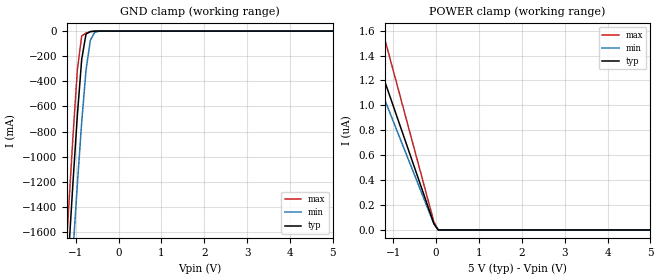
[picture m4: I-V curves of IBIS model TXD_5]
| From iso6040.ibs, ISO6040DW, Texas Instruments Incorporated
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|   TXD_5 Model
[Model]   TXD_5
Model_type   Input
|Signals   TXD
Vinl =  1.500V
Vinh =  3.500V
|   typ   min   max
C_comp   1.3pF   1.1pF   1.5pF
|   typ   min   max
[Temperature Range]   27   -55   150
[Voltage range]   5.0V   4.5V   5.5V
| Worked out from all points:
|   GND clamp passes 1 mA (typ) near -0.57 V on its own axis
[GND_clamp]
|Voltage   I(typ)   I(min)   I(max)
-5V       -18.88A    -18.42A    -19.4A
-1.263V   -2.337A    -2.857A    -2.002A
-1.162V   -1.76A     -2.296A    -1.406A
-1.061V   -1.199A    -1.748A    -830.6mA
-960mV    -669.8mA   -1.219A    -310.2mA
-859mV    -225.7mA   -725.6mA   -38.72mA
-758mV    -23.33mA   -311.2mA   -16.13mA
-657mV    -3.585mA   -73.04mA   -5.621mA
-556mV    -561.7uA   -9.428mA   -751.6uA
-455mV    -35.58uA   -731.5uA   -23.6uA
5V        0A         0A         -640.1nA
[POWER_clamp]
|Voltage   I(typ)   I(min)   I(max)
-5V       4.982uA    4.351uA    6.403uA
-1.868V   1.861uA    1.627uA    2.392uA
-1.767V   1.761uA    1.54uA     2.263uA
-1.666V   1.66uA     1.452uA    2.133uA
-1.565V   1.559uA    1.364uA    2.004uA
-1.262V   1.258uA    1.101uA    1.616uA
-1.161V   1.157uA    1.013uA    1.487uA
-50mV     49.91nA    47.77nA    64.12nA
51mV      0A         0A         0A
5V        0A         0A         0A
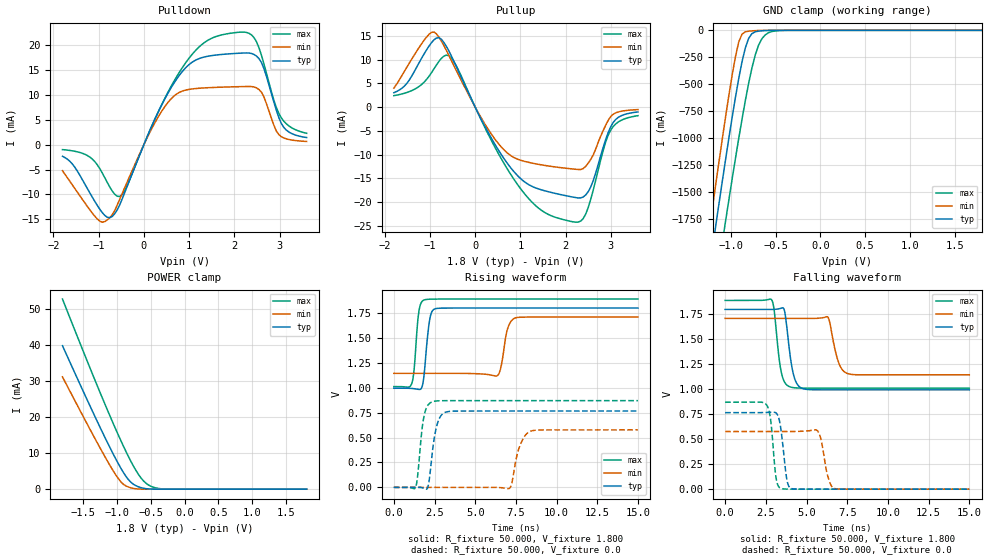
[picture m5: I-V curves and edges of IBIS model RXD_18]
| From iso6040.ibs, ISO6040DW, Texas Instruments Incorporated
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|   RXD_18 Model
[Model]   RXD_18
Model_type   3-state
| Signals   RXD
| variable   typ   min   max
C_comp   2.1pF   1.7pF   2.5pF
|   typ   min   max
[Temperature Range]   25.0   -55   150
[Voltage range]   1.8V   1.71V   1.89V
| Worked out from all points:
|   slope of the pulldown table from 0 to 0.27 V, typ, clamps not added: 47.8 ohm
|   slope of the pullup table from 0 to 0.27 V, typ, clamps not added: 53.6 ohm
|   GND clamp passes 1 mA (typ) near -0.57 V on its own axis
|   POWER clamp passes 1 mA (typ) near -0.72 V on its own axis
|   rising waveform, R_fixture 50.000, V_fixture 1.800: 20-80 % time 287ps typ, 355ps min, 252ps max; typ from 0.995 V to 1.8 V
|   rising waveform, R_fixture 50.000, V_fixture 0.0: 20-80 % time 395ps typ, 530ps min, 333ps max; typ from 0 V to 0.766 V
|   falling waveform, R_fixture 50.000, V_fixture 1.800: 20-80 % time 410ps typ, 485ps min, 366ps max; typ from 1.8 V to 0.995 V
|   falling waveform, R_fixture 50.000, V_fixture 0.0: 20-80 % time 325ps typ, 398ps min, 288ps max; typ from 0.766 V to 0 V
[Pulldown]
|Voltage   I(typ)   I(min)   I(max)
-1.8V     -2.335mA   -5.244mA   -989.9uA
-1.03V    -12.24mA   -14.97mA   -4.049mA
-700mV    -14.46mA   -14.1mA    -9.325mA
-425mV    -9.688mA   -8.683mA   -9.257mA
180mV     3.852mA    3.341mA    3.855mA
620mV     11.74mA    9.4mA      12.04mA
1.28V     17.53mA    11.41mA    20.16mA
2.105V    18.43mA    11.69mA    22.65mA
2.38V     18.38mA    11.71mA    22.13mA
2.6V      16.56mA    10.59mA    18.04mA
3.04V     4.29mA     1.616mA    5.413mA
3.6V      1.438mA    652.1uA    2.296mA
[Pullup]
|Voltage   I(typ)   I(min)   I(max)
-1.8V     3.041mA    4.007mA    2.417mA
-1.515V   4.975mA    8.377mA    3.081mA
-1.075V   12.1mA     14.79mA    5.848mA
-800mV    14.65mA    14.74mA    9.683mA
-470mV    9.632mA    8.733mA    9.587mA
630mV     -10.76mA   -8.948mA   -11.76mA
1.4V      -17.26mA   -12.07mA   -21.3mA
2.225V    -19.09mA   -13.12mA   -24.28mA
2.39V     -18.95mA   -12.95mA   -23.5mA
2.555V    -16.85mA   -11.04mA   -19.46mA
2.995V    -4.181mA   -2.009mA   -4.878mA
3.6V      -1.015mA   -518.7uA   -1.803mA
[GND_clamp]
|Voltage   I(typ)   I(min)   I(max)
-1.8V     -5.55A     -5.263A    -6.015A
-1.245V   -2.254A    -1.881A    -2.805A
-1.208V   -2.04A     -1.662A    -2.596A
-1.171V   -1.829A    -1.444A    -2.389A
-1.06V    -1.206A    -809.9mA   -1.779A
-986mV    -811.2mA   -418.7mA   -1.384A
-912mV    -448.5mA   -108.4mA   -1.005A
-838mV    -162.4mA   -13.59mA   -652mA
-764mV    -29.97mA   -5.269mA   -347.9mA
-690mV    -7.462mA   -1.484mA   -136.9mA
-542mV    -545uA     -4.781uA   -11.14mA
1.8V      0A         0A         0A
[POWER_clamp]
|Voltage   I(typ)   I(min)   I(max)
-1.8V     39.81mA    31.16mA    52.76mA
-1.493V   27.11mA    20.12mA    38.23mA
-1.234V   16.69mA    11.05mA    26.29mA
-1.086V   11.01mA    6.141mA    19.71mA
-975mV    7.015mA    2.889mA    14.96mA
-901mV    4.615mA    1.347mA    11.92mA
-790mV    1.893mA    366.5uA    7.681mA
-679mV    650uA      40.99uA    4.075mA
-568mV    138uA      1.396uA    1.643mA
-457mV    11.68uA    20.67nA    519.2uA
-272mV    53.44nA    77.19pA    26.85uA
1.8V      0A         0A         0A
[Ramp]
| variable   typ   min   max
dV/dt_r   0.460/0.395n   0.346/0.528n   0.522/0.333n
dV/dt_f   0.483/0.409n   0.339/0.484n   0.527/0.366n
R_load = 50.000
[Rising Waveform]
R_fixture= 50.000
V_fixture= 1.800
V_fixture_min= 1.710
V_fixture_max= 1.890
|time   V(typ)   V(min)   V(max)
0s        994.8mV    1.144V     1.012V
1.111ns   992.6mV    1.145V     1.046V
1.544ns   982.8mV    1.145V     1.769V
1.867ns   1.141V     1.145V     1.881V
2.193ns   1.672V     1.145V     1.889V
2.573ns   1.794V     1.145V     1.89V
6.36ns    1.8V       1.122V     1.89V
6.998ns   1.8V       1.597V     1.89V
7.508ns   1.8V       1.703V     1.89V
15ns      1.8V       1.71V      1.89V
[Rising Waveform]
R_fixture= 50.000
V_fixture= 0.0
V_fixture_min= 0.0
V_fixture_max= 0.0
|time   V(typ)   V(min)   V(max)
0s        3.665nV    1.985nV    1.128uV
1.339ns   158.3uV    -9.392nV   995.5uV
1.849ns   -8.797mV   -29.83nV   709.4mV
2.349ns   325.9mV    -65.49nV   857.4mV
2.698ns   651mV      -116.4nV   867.9mV
3.268ns   758.5mV    -227.3nV   870.1mV
7.107ns   766.2mV    -9.832mV   870.4mV
7.732ns   766.2mV    411.7mV    870.4mV
8.452ns   766.2mV    566.5mV    870.4mV
15ns      766.2mV    577.1mV    870.4mV
[Falling Waveform]
R_fixture= 50.000
V_fixture= 1.800
V_fixture_min= 1.710
V_fixture_max= 1.890
|time   V(typ)   V(min)   V(max)
0s        1.8V       1.71V      1.89V
2.855ns   1.8V       1.71V      1.896V
3.37ns    1.809V     1.71V      1.244V
3.62ns    1.8V       1.71V      1.081V
3.98ns    1.353V     1.71V      1.025V
4.52ns    1.032V     1.71V      1.013V
6.31ns    994.8mV    1.722V     1.012V
6.948ns   994.8mV    1.279V     1.012V
7.518ns   994.8mV    1.158V     1.012V
15ns      994.8mV    1.145V     1.012V
[Falling Waveform]
R_fixture= 50.000
V_fixture= 0.0
V_fixture_min= 0.0
V_fixture_max= 0.0
|time   V(typ)   V(min)   V(max)
0s        766.2mV    577.1mV    870.4mV
2.565ns   768.3mV    577.1mV    838.8mV
2.784ns   770.1mV    577.1mV    706mV
3.132ns   762.2mV    577.1mV    110.3mV
3.425ns   599.7mV    577.1mV    7.388mV
3.779ns   108.5mV    577.1mV    853.8uV
4.046ns   7.887mV    577.4mV    232.5uV
5.689ns   12.87uV    581.8mV    16.19uV
6.703ns   11.96uV    7.317mV    15.94uV
15ns      11.4uV     9.467uV    15.29uV
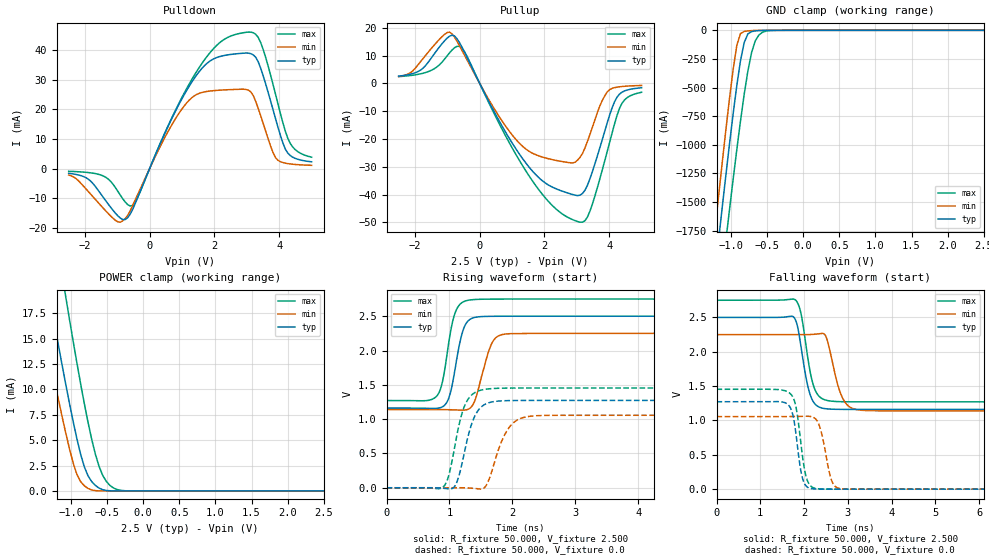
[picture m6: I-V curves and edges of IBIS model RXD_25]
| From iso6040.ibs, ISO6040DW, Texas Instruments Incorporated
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|   RXD_25 Model
[Model]   RXD_25
Model_type   3-state
| Signals   RXD
| variable   typ   min   max
C_comp   2.1pF   1.7pF   2.5pF
|   typ   min   max
[Temperature Range]   25.0   -55   150
[Voltage range]   2.5V   2.25V   2.75V
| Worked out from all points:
|   slope of the pulldown table from 0 to 0.375 V, typ, clamps not added: 39 ohm
|   slope of the pullup table from 0 to 0.375 V, typ, clamps not added: 43.6 ohm
|   GND clamp passes 1 mA (typ) near -0.57 V on its own axis
|   POWER clamp passes 1 mA (typ) near -0.72 V on its own axis
|   rising waveform, R_fixture 50.000, V_fixture 2.500: 20-80 % time 168ps typ, 202ps min, 165ps max; typ from 1.16 V to 2.5 V
|   rising waveform, R_fixture 50.000, V_fixture 0.0: 20-80 % time 216ps typ, 261ps min, 211ps max; typ from 0 V to 1.27 V
|   falling waveform, R_fixture 50.000, V_fixture 2.500: 20-80 % time 223ps typ, 268ps min, 228ps max; typ from 2.5 V to 1.16 V
|   falling waveform, R_fixture 50.000, V_fixture 0.0: 20-80 % time 166ps typ, 203ps min, 185ps max; typ from 1.27 V to 0 V
[Pulldown]
|Voltage   I(typ)   I(min)   I(max)
-2.5V     -1.625mA   -2.206mA   -947.1uA
-1.892V   -3.611mA   -7.805mA   -1.365mA
-1.36V    -10.84mA   -14.29mA   -2.937mA
-752mV    -17.27mA   -16.94mA   -11.38mA
-448mV    -11.9mA    -10.69mA   -11.47mA
1.224V    27.93mA    23.18mA    28.67mA
2.136V    37.82mA    26.51mA    42.35mA
3.048V    39.08mA    26.51mA    46.2mA
3.428V    33.95mA    17.88mA    42.64mA
3.884V    16.98mA    3.713mA    25.25mA
4.34V     4.393mA    1.548mA    8.519mA
5V        2.273mA    1.082mA    3.83mA
[Pullup]
|Voltage   I(typ)   I(min)   I(max)
-2.5V     2.588mA    2.465mA    2.421mA
-1.764V   5.301mA    8.681mA    3.583mA
-1.004V   16.25mA    18.26mA    9.886mA
-548mV    13.08mA    11.9mA     12.68mA
592mV     -13.29mA   -11.78mA   -14.23mA
1.352V    -27.51mA   -22.93mA   -30.14mA
2.264V    -37.45mA   -27.51mA   -44.19mA
3.1V      -40.23mA   -26.6mA    -49.96mA
3.404V    -34.37mA   -18.4mA    -46.03mA
3.936V    -14.32mA   -3.13mA    -24.63mA
4.392V    -3.202mA   -1.146mA   -7.23mA
5V        -1.582mA   -764.8uA   -3.201mA
[GND_clamp]
|Voltage   I(typ)   I(min)   I(max)
-2.5V     -9.36A     -9.468A    -9.252A
-1.225V   -2.138A    -1.762A    -2.692A
-1.174V   -1.846A    -1.462A    -2.406A
-1.123V   -1.557A    -1.166A    -2.123A
-1.072V   -1.272A    -876.6mA   -1.844A
-1.021V   -995.4mA   -598.5mA   -1.569A
-919mV    -480.7mA   -130.4mA   -1.04A
-817mV    -106.9mA   -9.777mA   -559.2mA
-715mV    -11.09mA   -2.487mA   -194.8mA
-664mV    -5.107mA   -761uA     -92.14mA
-511mV    -239.3uA   -922.2nA   -6.444mA
2.5V      0A         0A         0A
[POWER_clamp]
|Voltage   I(typ)   I(min)   I(max)
-2.5V     69.34mA    56.76mA    86.62mA
-1.478V   26.5mA     19.58mA    37.53mA
-1.427V   24.42mA    17.77mA    35.15mA
-1.325V   20.31mA    14.19mA    30.44mA
-1.274V   18.27mA    12.42mA    28.11mA
-1.07V    10.41mA    5.638mA    19.01mA
-917mV    5.107mA    1.609mA    12.57mA
-764mV    1.488mA    247.4uA    6.764mA
-662mV    538.5uA    25.96uA    3.612mA
-560mV    119uA      1.058uA    1.524mA
-356mV    729.5nA    369.7pA    125.3uA
2.5V      0A         0A         0A
[Ramp]
| variable   typ   min   max
dV/dt_r   0.764/0.216n   0.634/0.261n   0.872/0.210n
dV/dt_f   0.803/0.224n   0.666/0.269n   0.887/0.228n
R_load = 50.000
[Rising Waveform]
R_fixture= 50.000
V_fixture= 2.500
V_fixture_min= 2.250
V_fixture_max= 2.750
|time   V(typ)   V(min)   V(max)
0s        1.161V     1.141V     1.271V
726ps     1.156V     1.14V      1.289V
843ps     1.164V     1.14V      1.405V
929ps     1.209V     1.138V     1.744V
1.094ns   1.752V     1.134V     2.556V
1.21ns    2.276V     1.131V     2.704V
1.338ns   2.461V     1.168V     2.738V
1.672ns   2.499V     2.101V     2.749V
1.892ns   2.5V       2.241V     2.75V
15ns      2.5V       2.25V      2.75V
[Rising Waveform]
R_fixture= 50.000
V_fixture= 0.0
V_fixture_min= 0.0
V_fixture_max= 0.0
|time   V(typ)   V(min)   V(max)
0s        3.613nV    2.041nV    1.082uV
866ps     -4.429mV   81.09uV    -8.397mV
971ps     -14.44mV   122.1uV    124.7mV
1.064ns   85.77uV    175.5uV    499.1mV
1.268ns   637.6mV    -1.639mV   1.246V
1.42ns    1.074V     -11.73mV   1.395V
1.613ns   1.235V     84.37mV    1.44V
1.944ns   1.27V      871.9mV    1.453V
2.374ns   1.273V     1.05V      1.454V
15ns      1.273V     1.057V     1.454V
[Falling Waveform]
R_fixture= 50.000
V_fixture= 2.500
V_fixture_min= 2.250
V_fixture_max= 2.750
|time   V(typ)   V(min)   V(max)
0s        2.5V       2.25V      2.75V
1.813ns   2.449V     2.25V      2.748V
1.932ns   2.063V     2.25V      2.548V
2.149ns   1.356V     2.252V     1.673V
2.31ns    1.207V     2.26V      1.376V
2.476ns   1.173V     2.248V     1.3V
2.567ns   1.167V     2.073V     1.286V
2.881ns   1.161V     1.323V     1.273V
3.301ns   1.161V     1.149V     1.271V
15ns      1.161V     1.141V     1.271V
[Falling Waveform]
R_fixture= 50.000
V_fixture= 0.0
V_fixture_min= 0.0
V_fixture_max= 0.0
|time   V(typ)   V(min)   V(max)
0s        1.273V     1.057V     1.454V
1.696ns   1.173V     1.058V     1.383V
1.818ns   784.7mV    1.059V     1.185V
1.978ns   128.7mV    1.061V     408.3mV
2.104ns   18.83mV    1.061V     84.37mV
2.297ns   1.833mV    995.1mV    7.505mV
2.399ns   726.6uV    813.4mV    2.802mV
2.625ns   124.8uV    132.4mV    493.8uV
2.819ns   38.6uV     8.003mV    140uV
15ns      13.64uV    11.87uV    18.83uV
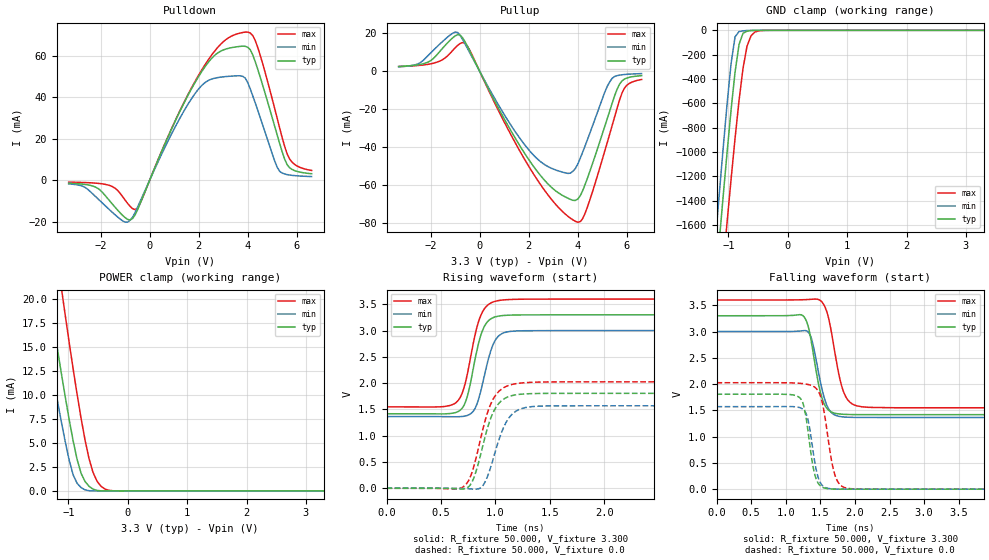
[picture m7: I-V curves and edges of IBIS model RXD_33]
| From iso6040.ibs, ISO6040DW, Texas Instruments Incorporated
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|   RXD_33 Model
[Model]   RXD_33
Model_type   3-state
| Signals   RXD
Vmeas = 2.2V   |Reference voltage for timing measurements
Cref = 15pF   |Timing specification test load capacitance value
Vref = 0   |Timing specification test load voltage; GND
| variable   typ   min   max
C_comp   2.1pF   1.7pF   2.5pF
|   typ   min   max
[Temperature Range]   25.0   -55   150
[Voltage range]   3.3V   3.0V   3.6V
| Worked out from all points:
|   slope of the pulldown table from 0 to 0.495 V, typ, clamps not added: 35.3 ohm
|   slope of the pullup table from 0 to 0.495 V, typ, clamps not added: 38.9 ohm
|   GND clamp passes 1 mA (typ) near -0.56 V on its own axis
|   POWER clamp passes 1 mA (typ) near -0.72 V on its own axis
|   rising waveform, R_fixture 50.000, V_fixture 3.300: 20-80 % time 120ps typ, 123ps min, 130ps max; typ from 1.42 V to 3.3 V
|   rising waveform, R_fixture 50.000, V_fixture 0.0: 20-80 % time 152ps typ, 156ps min, 161ps max; typ from 0 V to 1.81 V
|   falling waveform, R_fixture 50.000, V_fixture 3.300: 20-80 % time 157ps typ, 161ps min, 179ps max; typ from 3.3 V to 1.42 V
|   falling waveform, R_fixture 50.000, V_fixture 0.0: 20-80 % time 122ps typ, 119ps min, 151ps max; typ from 1.81 V to 0 V
[Pulldown]
|Voltage   I(typ)   I(min)   I(max)
-3.3V     -1.393mA   -1.747mA   -927.3uA
-2.2V     -3.331mA   -7.915mA   -1.397mA
-1.6V     -10.36mA   -14.61mA   -2.646mA
-700mV    -18.5mA    -17.91mA   -13.66mA
-400mV    -11.6mA    -10.55mA   -11.49mA
2V        50.13mA    44.09mA    50.76mA
2.8V      61.6mA     49.56mA    64.41mA
3.9V      64.58mA    49.21mA    71.45mA
4.4V      53.72mA    33.93mA    64.23mA
5.3V      17.64mA    4.279mA    25.12mA
5.8V      5.234mA    2.368mA    8.768mA
6.6V      3.148mA    1.78mA     4.728mA
[Pullup]
|Voltage   I(typ)   I(min)   I(max)
-3.3V     2.528mA    2.36mA     2.481mA
-2.1V     4.845mA    8.282mA    3.66mA
-1V       18.57mA    20.6mA     12.32mA
-600mV    15.62mA    14.5mA     14.73mA
1V        -24.99mA   -22.73mA   -26.63mA
2.2V      -50.12mA   -44.19mA   -54.13mA
3.6V      -66.81mA   -53.75mA   -76.32mA
4V        -67.23mA   -48.79mA   -79.4mA
4.4V      -55.98mA   -35.72mA   -71.14mA
5.4V      -16.86mA   -3.719mA   -28.55mA
5.9V      -4.12mA    -1.716mA   -8.91mA
6.6V      -2.323mA   -1.24mA    -4.34mA
[GND_clamp]
|Voltage   I(typ)   I(min)   I(max)
-3.3V     -12.47A    -12.69A    -12.28A
-1.223V   -2.127A    -1.75A     -2.681A
-1.156V   -1.743A    -1.357A    -2.306A
-1.089V   -1.367A    -972.1mA   -1.937A
-1.022V   -1.001A    -603.8mA   -1.575A
-955mV    -653.8mA   -272.6mA   -1.223A
-888mV    -343.9mA   -53.17mA   -886.9mA
-821mV    -116.4mA   -10.32mA   -576.6mA
-687mV    -7.135mA   -1.384mA   -131mA
-620mV    -2.623mA   -170.6uA   -45.53mA
-486mV    -113.9uA   -230.3nA   -4.203mA
3.3V      0A         0A         0A
[POWER_clamp]
|Voltage   I(typ)   I(min)   I(max)
-3.3V     103.5mA    86.29mA    125.9mA
-1.524V   28.38mA    21.22mA    39.68mA
-1.457V   25.64mA    18.84mA    36.55mA
-1.323V   20.23mA    14.12mA    30.35mA
-1.122V   12.36mA    7.298mA    21.29mA
-1.055V   9.86mA     5.174mA    18.36mA
-921mV    5.233mA    1.682mA    12.73mA
-787mV    1.841mA    351.3uA    7.574mA
-720mV    983.4uA    108.5uA    5.305mA
-519mV    51.34uA    237.9nA    1.021mA
-318mV    230.7nA    159.6pA    64.62uA
3.3V      0A         0A         0A
[Ramp]
| variable   typ   min   max
dV/dt_r   1.084/0.152n   0.942/0.156n   1.215/0.161n
dV/dt_f   1.129/0.157n   0.981/0.161n   1.231/0.179n
R_load = 50.000
[Rising Waveform]
R_fixture= 50.000
V_fixture= 3.300
V_fixture_min= 3.000
V_fixture_max= 3.600
|time   V(typ)   V(min)   V(max)
0s        1.418V     1.364V     1.549V
645ps     1.449V     1.361V     1.643V
692ps     1.517V     1.365V     1.797V
736ps     1.708V     1.382V     2.116V
807ps     2.393V     1.497V     2.86V
870ps     2.938V     1.887V     3.309V
974ps     3.242V     2.712V     3.541V
1.026ns   3.275V     2.891V     3.571V
1.1ns     3.291V     2.972V     3.588V
15ns      3.3V       3V         3.6V
[Rising Waveform]
R_fixture= 50.000
V_fixture= 0.0
V_fixture_min= 0.0
V_fixture_max= 0.0
|time   V(typ)   V(min)   V(max)
0s        4.892nV    2.133nV    1.145uV
700ps     -15.49mV   -3.529mV   21.36mV
789ps     134.2mV    -14.5mV    326.3mV
874ps     720.9mV    25.56mV    1.028V
928ps     1.151V     231.8mV    1.444V
984ps     1.462V     590.8mV    1.714V
1.049ns   1.653V     1.023V     1.875V
1.112ns   1.736V     1.302V     1.949V
1.276ns   1.796V     1.536V     2.01V
15ns      1.806V     1.57V      2.026V
[Falling Waveform]
R_fixture= 50.000
V_fixture= 3.300
V_fixture_min= 3.000
V_fixture_max= 3.600
|time   V(typ)   V(min)   V(max)
0s        3.3V       3V         3.6V
1.247ns   3.304V     3.015V     3.605V
1.363ns   2.86V      2.902V     3.613V
1.502ns   1.839V     2.037V     3.589V
1.62ns    1.504V     1.528V     3.253V
1.768ns   1.432V     1.386V     2.185V
1.832ns   1.425V     1.374V     1.867V
1.931ns   1.421V     1.368V     1.651V
2.101ns   1.418V     1.365V     1.567V
15ns      1.418V     1.364V     1.549V
[Falling Waveform]
R_fixture= 50.000
V_fixture= 0.0
V_fixture_min= 0.0
V_fixture_max= 0.0
|time   V(typ)   V(min)   V(max)
0s        1.806V     1.57V      2.026V
1.195ns   1.749V     1.555V     2.016V
1.255ns   1.611V     1.512V     2.008V
1.308ns   1.239V     1.388V     1.996V
1.427ns   246.7mV    465.1mV    1.933V
1.531ns   36.83mV    68.88mV    1.632V
1.709ns   2.227mV    2.974mV    278.5mV
1.783ns   894.1uV    1.021mV    87.65mV
1.92ns    209.2uV    189.8uV    11.32mV
15ns      15.73uV    13.45uV    22.02uV
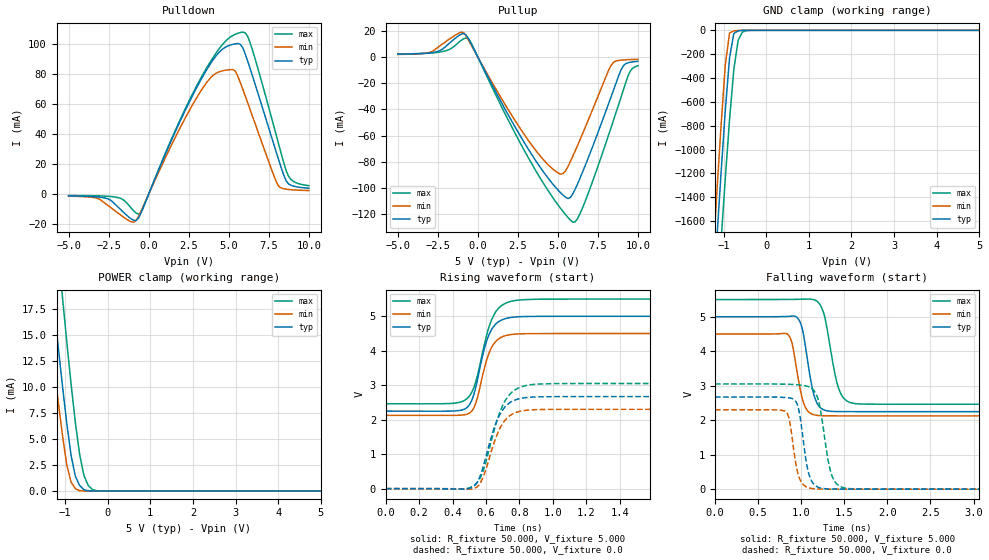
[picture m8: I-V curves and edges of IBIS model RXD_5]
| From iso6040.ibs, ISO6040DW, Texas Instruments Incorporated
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|   RXD_5 Model
[Model]   RXD_5
Model_type   3-state
Vmeas = 2.2V   |Reference voltage for timing measurements
Cref = 15pF   |Timing specification test load capacitance value
Vref = 0   |Timing specification test load voltage; GND
| variable   typ   min   max
C_comp   2.1pF   1.7pF   2.5pF
|   typ   min   max
[Temperature Range]   25.0   -55   150
[Voltage range]   5.0V   4.5V   5.5V
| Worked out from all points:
|   slope of the pulldown table from 0 to 0.75 V, typ, clamps not added: 38.8 ohm
|   slope of the pullup table from 0 to 0.75 V, typ, clamps not added: 41.8 ohm
|   GND clamp passes 1 mA (typ) near -0.56 V on its own axis
|   POWER clamp passes 1 mA (typ) near -0.71 V on its own axis
|   rising waveform, R_fixture 50.000, V_fixture 5.000: 20-80 % time 85.6ps typ, 80.4ps min, 96.1ps max; typ from 2.25 V to 5 V
|   rising waveform, R_fixture 50.000, V_fixture 0.0: 20-80 % time 105ps typ, 101ps min, 113ps max; typ from 0 V to 2.67 V
|   falling waveform, R_fixture 50.000, V_fixture 5.000: 20-80 % time 112ps typ, 105ps min, 135ps max; typ from 5 V to 2.25 V
|   falling waveform, R_fixture 50.000, V_fixture 0.0: 20-80 % time 95.8ps typ, 87ps min, 119ps max; typ from 2.67 V to 0 V
[Pulldown]
|Voltage   I(typ)   I(min)   I(max)
-5V       -1.037mA   -1.214mA   -788.1uA
-2.584V   -2.851mA   -7.029mA   -1.283mA
-1.074V   -16.47mA   -18.37mA   -9.34mA
-470mV    -12.26mA   -11.15mA   -11.94mA
1.946V    48.19mA    43.78mA    49.11mA
3.758V    85.17mA    76.21mA    86.54mA
5.268V    99.87mA    82.99mA    105.8mA
5.872V    97.76mA    70.24mA    108mA
6.476V    79.2mA     52.29mA    96.4mA
8.137V    22.45mA    5.214mA    32.8mA
8.741V    6.971mA    3.227mA    11.94mA
10V       4.07mA     2.512mA    5.759mA
[Pullup]
|Voltage   I(typ)   I(min)   I(max)
-5V       2.195mA    1.994mA    2.343mA
-2.533V   4.197mA    6.987mA    3.547mA
-1.023V   17.52mA    19.05mA    12.9mA
-570mV    13.73mA    12.61mA    13.71mA
4.111V    -87.84mA   -78.53mA   -96.62mA
5.168V    -103.5mA   -89.35mA   -115.5mA
5.923V    -104.5mA   -75.86mA   -126mA
6.527V    -88.13mA   -58.84mA   -115.4mA
8.339V    -29.71mA   -6.022mA   -53.07mA
9.094V    -6.515mA   -2.192mA   -24.88mA
9.547V    -3.88mA    -1.909mA   -10.1mA
10V       -3.261mA   -1.75mA    -6.597mA
[GND_clamp]
|Voltage   I(typ)   I(min)   I(max)
-5V       -19.06A    -19.48A    -18.7A
-1.263V   -2.358A    -1.988A    -2.906A
-1.162V   -1.777A    -1.392A    -2.339A
-1.061V   -1.212A    -815.5mA   -1.784A
-960mV    -678.8mA   -295mA     -1.249A
-859mV    -231.2mA   -22.05mA   -748.6mA
-758mV    -26.06mA   -4.878mA   -326.7mA
-657mV    -4.614mA   -619.2uA   -82.53mA
-556mV    -760.5uA   -9.69uA    -14.38mA
-455mV    -42.02uA   -39.64nA   -2.488mA
5V        0A         0A         0A
[POWER_clamp]
|Voltage   I(typ)   I(min)   I(max)
-5V       176.6mA    149.4mA    210.1mA
-1.464V   25.93mA    19.09mA    36.87mA
-1.363V   21.83mA    15.52mA    32.19mA
-1.262V   17.8mA     12.01mA    27.56mA
-1.06V    10.04mA    5.328mA    18.58mA
-959mV    6.473mA    2.492mA    14.29mA
-858mV    3.393mA    836.2uA    10.23mA
-757mV    1.394mA    220.2uA    6.524mA
-656mV    502.3uA    21.96uA    3.456mA
-454mV    10.82uA    18.37nA    501.2uA
-252mV    27.84nA    146.1pA    18.12uA
5V        0A         0A         0A
[Ramp]
| variable   typ   min   max
dV/dt_r   1.602/0.105n   1.381/0.101n   1.831/0.113n
dV/dt_f   1.651/0.112n   1.424/0.105n   1.823/0.135n
R_load = 50.000
[Rising Waveform]
R_fixture= 50.000
V_fixture= 5.000
V_fixture_min= 4.500
V_fixture_max= 5.500
|time   V(typ)   V(min)   V(max)
0s        2.248V     2.126V     2.462V
475ps     2.314V     2.146V     2.57V
507ps     2.48V      2.213V     2.73V
536ps     2.877V     2.441V     3.061V
589ps     4.042V     3.457V     4.158V
615ps     4.431V     3.893V     4.643V
639ps     4.66V      4.141V     4.952V
712ps     4.927V     4.433V     5.367V
824ps     4.993V     4.494V     5.482V
15ns      5V         4.5V       5.5V
[Rising Waveform]
R_fixture= 50.000
V_fixture= 0.0
V_fixture_min= 0.0
V_fixture_max= 0.0
|time   V(typ)   V(min)   V(max)
0s        7.484nV    3.561nV    2.363uV
443ps     -12.35mV   -6.064mV   -9.918mV
530ps     81.6mV     9.02mV     99.52mV
553ps     227.1mV    78.15mV    215.6mV
582ps     623.4mV    326.8mV    492.7mV
645ps     1.705V     1.282V     1.623V
701ps     2.292V     1.899V     2.42V
772ps     2.568V     2.196V     2.861V
915ps     2.663V     2.295V     3.035V
15ns      2.671V     2.301V     3.051V
[Falling Waveform]
R_fixture= 50.000
V_fixture= 5.000
V_fixture_min= 4.500
V_fixture_max= 5.500
|time   V(typ)   V(min)   V(max)
0s        5V         4.5V       5.5V
828ps     5.008V     4.514V     5.502V
894ps     5.02V      4.233V     5.504V
947ps     4.989V     3.47V      5.506V
1.047ns   4.169V     2.386V     5.512V
1.186ns   2.483V     2.14V      5.444V
1.274ns   2.289V     2.128V     4.989V
1.444ns   2.25V      2.126V     2.86V
1.633ns   2.249V     2.126V     2.479V
15ns      2.249V     2.126V     2.462V
[Falling Waveform]
R_fixture= 50.000
V_fixture= 0.0
V_fixture_min= 0.0
V_fixture_max= 0.0
|time   V(typ)   V(min)   V(max)
0s        2.671V     2.301V     3.051V
807ps     2.661V     2.269V     3.045V
858ps     2.647V     2.057V     3.041V
917ps     2.6V       1.079V     3.034V
989ps     2.075V     262.5mV    3.02V
1.119ns   246.8mV    21.91mV    2.928V
1.206ns   47.99mV    4.301mV    2.516V
1.358ns   3.061mV    281.3uV    381.9mV
1.604ns   63.08uV    22.83uV    6.489mV
15ns      22.07uV    18.19uV    32.61uV
